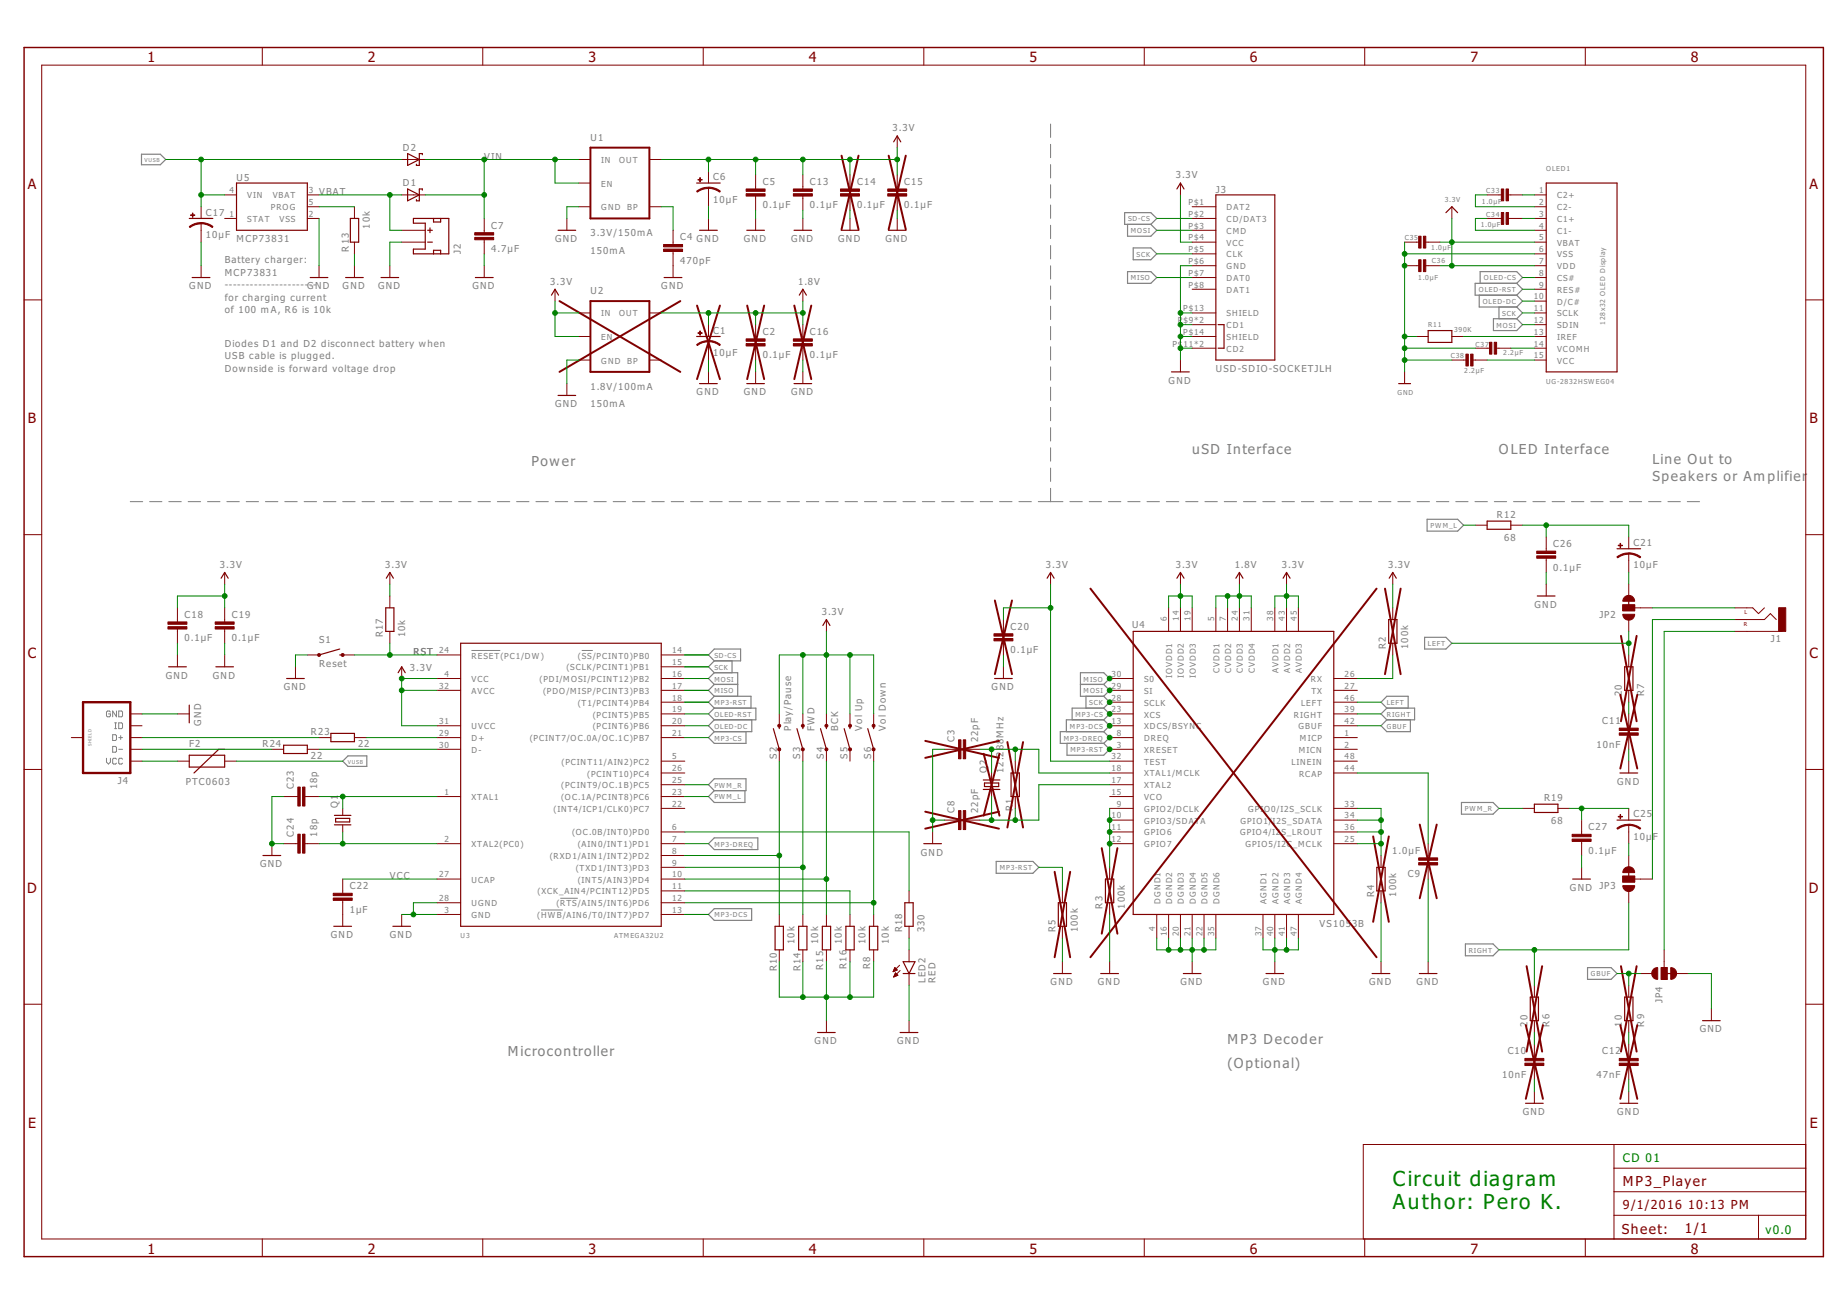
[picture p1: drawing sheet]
<svg xmlns="http://www.w3.org/2000/svg" width="297mm" height="210mm" viewBox="0 0 297 210" stroke-linecap="round" stroke-linejoin="round" font-family="sans-serif">
<defs><g id="words">
<g font-size="4" fill="#008000">
<text x="224" y="190.7">Circuit diagram</text>
<text x="224" y="194.5">Author: Pero K.</text>
</g>
<g font-size="2.8" fill="#800000">
<text x="23.7" y="10">1</text>
<text x="59.2" y="10">2</text>
<text x="94.6" y="10">3</text>
<text x="130.1" y="10">4</text>
<text x="165.6" y="10">5</text>
<text x="201" y="10">6</text>
<text x="236.5" y="10">7</text>
<text x="271.9" y="10">8</text>
<text x="4.5" y="30.3">A</text>
<text x="291" y="30.3">A</text>
<text x="4.5" y="68.1">B</text>
<text x="291" y="68.1">B</text>
<text x="4.5" y="105.8">C</text>
<text x="291" y="105.8">C</text>
<text x="4.4" y="143.6">D</text>
<text x="290.9" y="143.6">D</text>
<text x="4.5" y="181.4">E</text>
<text x="291.1" y="181.4">E</text>
<text x="23.7" y="201.7">1</text>
<text x="59.2" y="201.7">2</text>
<text x="94.6" y="201.7">3</text>
<text x="130.1" y="201.7">4</text>
<text x="165.6" y="201.7">5</text>
<text x="201" y="201.7">6</text>
<text x="236.5" y="201.7">7</text>
<text x="271.9" y="201.7">8</text>
</g>
<g font-size="2.7" fill="#808080">
<text x="85.5" y="75">Power</text>
<text x="191.7" y="73.1">uSD Interface</text>
<text x="241.1" y="73.1">OLED Interface</text>
<text x="265.7" y="74.6">Line Out to</text>
<text x="265.7" y="77.4">Speakers or Amplifier</text>
<text x="197.4" y="168">MP3 Decoder</text>
<text x="81.7" y="169.9">Microcontroller</text>
<text x="197.4" y="171.8">(Optional)</text>
</g>
<g font-size="2.7" fill="#800000">
<text x="261" y="190.7">MP3_Player</text>
<text x="260.8" y="198.4">Sheet:</text>
<text x="271" y="198.3">1/1</text>
</g>
<g font-size="2.4" fill="#800000">
<text x="261" y="194.5">9/1/2016</text>
<text x="271.5" y="194.5">10:13 PM</text>
</g>
<g font-size="2.3" fill="#008000">
<text x="261" y="186.9">CD 01</text>
<text x="284" y="198.5">v0.0</text>
</g>
<g font-size="1.9" fill="#808080">
<text x="95" y="22.6">U1</text>
<text x="143.5" y="21.1">3.3V</text>
<text x="38" y="29.1">U5</text>
<text x="64.8" y="29.9">D1</text>
<text x="64.8" y="24.2">D2</text>
<text x="77.9" y="25.7">VIN</text>
<text x="114.7" y="29">C6</text>
<text x="122.7" y="29.7">C5</text>
<text x="130.3" y="29.7">C13</text>
<text x="137.8" y="29.7">C14</text>
<text x="145.4" y="29.7">C15</text>
<text x="189.1" y="28.7">3.3V</text>
<text x="33.1" y="34.7">C17</text>
<text x="51.3" y="31.3">VBAT</text>
<text x="114.7" y="32.6">10µF</text>
<text x="122.7" y="33.5">0.1µF</text>
<text x="130.3" y="33.5">0.1µF</text>
<text x="137.8" y="33.5">0.1µF</text>
<text x="145.4" y="33.5">0.1µF</text>
<text x="195.5" y="31">J3</text>
<text x="33.1" y="38.3">10µF</text>
<text x="38" y="38.9">MCP73831</text>
<text x="56.1" y="40.5" transform="rotate(-90 56.1 40.5)">R13</text>
<text x="59.5" y="36.8" transform="rotate(-90 59.5 36.8)">10k</text>
<text x="74.1" y="40.8" transform="rotate(-90 74.1 40.8)">J2</text>
<text x="79" y="40.6">4.7μF</text>
<text x="79" y="36.8">C7</text>
<text x="89.3" y="38.9">GND</text>
<text x="95" y="40.8">150mA</text>
<text x="95" y="38">3.3V/150mA</text>
<text x="109.4" y="38.7">C4 GND</text>
<text x="119.6" y="38.9">GND</text>
<text x="127.2" y="38.9">GND</text>
<text x="134.8" y="38.9">GND</text>
<text x="142.4" y="38.9">GND</text>
<text x="30.4" y="46.5">GND</text>
<text x="36.1" y="42.4">Battery charger:</text>
<text x="36.1" y="44.4">MCP73831</text>
<text x="36.1" y="46.3">--------------------G--ND</text>
<text x="55.1" y="46.5">GND</text>
<text x="60.8" y="46.5">GND</text>
<text x="76" y="46.5">GND</text>
<text x="88.5" y="45.8">3.3V</text>
<text x="95" y="47.3">U2</text>
<text x="106.3" y="46.5">GND</text>
<text x="109.4" y="42.4">470pF</text>
<text x="128.4" y="45.8">1.8V</text>
<text x="36.1" y="48.3">for charging current</text>
<text x="36.1" y="50.3">of 100 mA, R6 is 10k</text>
<text x="114.7" y="53.6">C1</text>
<text x="122.7" y="53.8">C2</text>
<text x="130.3" y="53.8">C16</text>
<text x="36.1" y="55.8">Diodes D1 and D2 disconnect battery when</text>
<text x="36.1" y="57.8">USB cable is plugged.</text>
<text x="36.1" y="59.8">Downside is forward voltage drop</text>
<text x="114.7" y="57.2">10µF</text>
<text x="122.7" y="57.6">0.1µF</text>
<text x="130.3" y="57.6">0.1µF</text>
<text x="195.5" y="59.8">USD-SDIO-SOCKETJLH</text>
<text x="89.3" y="65.5">GND</text>
<text x="95" y="65.5">150mA</text>
<text x="95" y="62.7">1.8V/100mA</text>
<text x="112" y="63.6">GND</text>
<text x="119.6" y="63.6">GND</text>
<text x="127.2" y="63.6">GND</text>
<text x="187.9" y="61.7">GND</text>
<text x="240.7" y="83.4">R12</text>
<text x="241.9" y="86.9">68</text>
<text x="249.8" y="88">C26</text>
<text x="262.7" y="87.8">C21</text>
<text x="35.4" y="91.3">3.3V</text>
<text x="61.9" y="91.3">3.3V</text>
<text x="168.2" y="91.3">3.3V</text>
<text x="189.1" y="91.3">3.3V</text>
<text x="198.6" y="91.3">1.8V</text>
<text x="206.2" y="91.3">3.3V</text>
<text x="223.2" y="91.3">3.3V</text>
<text x="249.8" y="91.8">0.1µF</text>
<text x="262.7" y="91.4">10µF</text>
<text x="29.7" y="99.4">C18</text>
<text x="37.3" y="99.4">C19</text>
<text x="132.1" y="98.9">3.3V</text>
<text x="162.5" y="101.3">C20</text>
<text x="182.1" y="101">U4</text>
<text x="246.8" y="97.8">GND</text>
<text x="257.2" y="99.4">JP2</text>
<text x="29.7" y="103.2">0.1µF</text>
<text x="37.3" y="103.2">0.1µF</text>
<text x="51.3" y="107.2">Reset</text>
<text x="51.3" y="103.5">S1</text>
<text x="61.6" y="102.5" transform="rotate(-90 61.6 102.5)">R17</text>
<text x="65.2" y="102.5" transform="rotate(-90 65.2 102.5)">10k</text>
<text x="66.5" y="105.4">RST</text>
<text x="162.5" y="105.1">0.1µF</text>
<text x="222.9" y="104.4" transform="rotate(-90 222.9 104.4)">R2</text>
<text x="226.5" y="104.4" transform="rotate(-90 226.5 104.4)">100k</text>
<text x="284.8" y="103.3">J1</text>
<text x="26.6" y="109.1">GND</text>
<text x="34.2" y="109.1">GND</text>
<text x="45.6" y="111">GND</text>
<text x="65.9" y="108">3.3V</text>
<text x="159.5" y="111">GND</text>
<text x="260.8" y="112" transform="rotate(-90 260.8 112)">20</text>
<text x="264.4" y="112" transform="rotate(-90 264.4 112)">R7</text>
<text x="32.3" y="116.7" transform="rotate(-90 32.3 116.7)">GND</text>
<text x="50" y="118.3">R23</text>
<text x="127.2" y="117.5" transform="rotate(-90 127.2 117.5)">Play/Pause</text>
<text x="131" y="117.5" transform="rotate(-90 131 117.5)">FWD</text>
<text x="134.8" y="117.5" transform="rotate(-90 134.8 117.5)">BCK</text>
<text x="138.7" y="117.5" transform="rotate(-90 138.7 117.5)">Vol Up</text>
<text x="142.5" y="117.5" transform="rotate(-90 142.5 117.5)">Vol Down</text>
<text x="153.5" y="119.4" transform="rotate(-90 153.5 119.4)">C3</text>
<text x="157.3" y="119.4" transform="rotate(-90 157.3 119.4)">22pF</text>
<text x="257.7" y="116.5">C11</text>
<text x="30.4" y="120.2">F2</text>
<text x="42.2" y="120.2">R24</text>
<text x="50" y="122">22</text>
<text x="57.6" y="120.2">22</text>
<text x="124.9" y="122" transform="rotate(-90 124.9 122)">S2</text>
<text x="128.7" y="122" transform="rotate(-90 128.7 122)">S3</text>
<text x="132.5" y="122" transform="rotate(-90 132.5 122)">S4</text>
<text x="136.3" y="122" transform="rotate(-90 136.3 122)">S5</text>
<text x="140.1" y="122" transform="rotate(-90 140.1 122)">S6</text>
<text x="158.7" y="124.3" transform="rotate(-90 158.7 124.3)">Q2</text>
<text x="161.4" y="124.3" transform="rotate(-90 161.4 124.3)">12.288MHz</text>
<text x="256.8" y="120.2">10nF</text>
<text x="19" y="126">J4</text>
<text x="29.9" y="126.2">PTC0603</text>
<text x="47.2" y="127" transform="rotate(-90 47.2 127)">C23</text>
<text x="51" y="127" transform="rotate(-90 51 127)">18p</text>
<text x="54.3" y="130" transform="rotate(-90 54.3 130)">Q1</text>
<text x="153.5" y="130.8" transform="rotate(-90 153.5 130.8)">C8</text>
<text x="157.3" y="130.8" transform="rotate(-90 157.3 130.8)">22pF</text>
<text x="162.9" y="130.5" transform="rotate(-90 162.9 130.5)">R1</text>
<text x="248.3" y="128.9">R19</text>
<text x="260.1" y="126.2">GND</text>
<text x="262.7" y="131.4">C25</text>
<text x="47.2" y="134.6" transform="rotate(-90 47.2 134.6)">C24</text>
<text x="51" y="134.6" transform="rotate(-90 51 134.6)">18p</text>
<text x="148.1" y="137.6">GND</text>
<text x="223.9" y="137.3">1.0µF</text>
<text x="249.5" y="132.5">68</text>
<text x="255.5" y="137.3">0.1µF</text>
<text x="255.5" y="133.5">C27</text>
<text x="262.7" y="135">10µ</text>
<text x="265.8" y="135">F</text>
<text x="41.8" y="139.5">GND</text>
<text x="56.2" y="143">C22</text>
<text x="62.7" y="141.4">VCC</text>
<text x="226.4" y="141.1">C9</text>
<text x="252.5" y="143.3">GND JP3</text>
<text x="56.2" y="146.8">1µF</text>
<text x="145.1" y="149.9" transform="rotate(-90 145.1 149.9)">R18</text>
<text x="148.7" y="149.9" transform="rotate(-90 148.7 149.9)">330</text>
<text x="169.7" y="149.9" transform="rotate(-90 169.7 149.9)">R5</text>
<text x="173.3" y="149.9" transform="rotate(-90 173.3 149.9)">100k</text>
<text x="177.3" y="146.1" transform="rotate(-90 177.3 146.1)">R3</text>
<text x="180.9" y="146.1" transform="rotate(-90 180.9 146.1)">100k</text>
<text x="212.2" y="149.2">VS1053B</text>
<text x="221" y="144.2" transform="rotate(-90 221 144.2)">R4</text>
<text x="224.6" y="144.2" transform="rotate(-90 224.6 144.2)">100k</text>
<text x="53.2" y="150.9">GND</text>
<text x="62.7" y="150.9">GND</text>
<text x="127.8" y="151.8" transform="rotate(-90 127.8 151.8)">10k</text>
<text x="131.6" y="151.8" transform="rotate(-90 131.6 151.8)">10k</text>
<text x="135.4" y="151.8" transform="rotate(-90 135.4 151.8)">10k</text>
<text x="136.2" y="155.8" transform="rotate(-90 136.2 155.8)">R16</text>
<text x="139.2" y="151.8" transform="rotate(-90 139.2 151.8)">10k</text>
<text x="139.9" y="155.8" transform="rotate(-90 139.9 155.8)">R8</text>
<text x="143" y="151.8" transform="rotate(-90 143 151.8)">10k</text>
<text x="125" y="156.2" transform="rotate(-90 125 156.2)">R10</text>
<text x="128.8" y="156.2" transform="rotate(-90 128.8 156.2)">R14</text>
<text x="132.4" y="156" transform="rotate(-90 132.4 156)">R15</text>
<text x="148.8" y="158.1" transform="rotate(-90 148.8 158.1)">LED2</text>
<text x="150.5" y="158.1" transform="rotate(-90 150.5 158.1)">RED</text>
<text x="169" y="158.5">GND</text>
<text x="176.6" y="158.5">GND</text>
<text x="189.8" y="158.5">GND</text>
<text x="203.1" y="158.5">GND</text>
<text x="220.2" y="158.5">GND</text>
<text x="227.8" y="158.5">GND</text>
<text x="267.4" y="161.3" transform="rotate(-90 267.4 161.3)">JP4</text>
<text x="131" y="168">GND</text>
<text x="144.3" y="168">GND</text>
<text x="245.6" y="165.1" transform="rotate(-90 245.6 165.1)">20</text>
<text x="249.2" y="165.1" transform="rotate(-90 249.2 165.1)">R6</text>
<text x="260.8" y="165.1" transform="rotate(-90 260.8 165.1)">10</text>
<text x="264.4" y="165.1" transform="rotate(-90 264.4 165.1)">R9</text>
<text x="273.4" y="166.1">GND</text>
<text x="241.6" y="173.4">10nF</text>
<text x="242.5" y="169.6">C10</text>
<text x="256.8" y="173.4">47nF</text>
<text x="257.7" y="169.6">C12</text>
<text x="244.9" y="179.4">GND</text>
<text x="260.1" y="179.4">GND</text>
</g>
<g font-size="1.6" fill="#808080">
<text x="96.7" y="26.2">IN</text>
<text x="99.6" y="26.2">OUT</text>
<text x="36.9" y="31.1">4</text>
<text x="36.9" y="34.9">1</text>
<text x="39.8" y="31.9">VIN</text>
<text x="39.8" y="35.7">STAT</text>
<text x="43.6" y="33.8">PROG</text>
<text x="43.9" y="31.9">VBAT</text>
<text x="44.9" y="35.7">VSS</text>
<text x="49.7" y="31.1">3</text>
<text x="49.7" y="33">5</text>
<text x="49.7" y="34.9">2</text>
<text x="96.7" y="33.8">GND BP</text>
<text x="96.7" y="30">EN</text>
<text x="191.2" y="34.9">P$2</text>
<text x="191.2" y="33">P$1</text>
<text x="197.3" y="35.7">CD/DAT3</text>
<text x="197.3" y="33.8">DAT2</text>
<text x="247.5" y="31.1">1</text>
<text x="247.5" y="33">2</text>
<text x="247.5" y="34.9">3</text>
<text x="250.4" y="31.9">C2+</text>
<text x="250.4" y="33.8">C2-</text>
<text x="250.4" y="35.7">C1+</text>
<text x="191.2" y="36.8">P$3</text>
<text x="191.2" y="38.7">P$4</text>
<text x="191.2" y="40.6">P$5</text>
<text x="197.3" y="37.6">CMD</text>
<text x="197.3" y="39.5">VCC</text>
<text x="197.3" y="41.4">CLK</text>
<text x="247.5" y="36.8">4</text>
<text x="247.5" y="38.7">5</text>
<text x="247.5" y="40.6">6</text>
<text x="250.4" y="37.6">C1-</text>
<text x="250.4" y="39.5">VBAT</text>
<text x="250.4" y="41.4">VSS</text>
<text x="191.2" y="42.5">P$6</text>
<text x="191.2" y="46.3">P$8</text>
<text x="191.2" y="44.4">P$7</text>
<text x="197.3" y="43.3">GND</text>
<text x="197.3" y="47.1">DAT1</text>
<text x="197.3" y="45.2">DAT0</text>
<text x="247.5" y="42.5">7</text>
<text x="247.5" y="44.4">8</text>
<text x="247.5" y="46.3">9</text>
<text x="250.4" y="43.3">VDD</text>
<text x="250.4" y="45.2">CS#</text>
<text x="250.4" y="47.1">RES#</text>
<text x="96.7" y="50.9">IN</text>
<text x="99.6" y="50.9">OUT</text>
<text x="189.4" y="52">P$9*2</text>
<text x="190.3" y="53.9">P$14</text>
<text x="190.3" y="50.1">P$13</text>
<text x="197.3" y="50.9">SHIELD</text>
<text x="197.3" y="52.8">CD1</text>
<text x="246.7" y="48.2">10</text>
<text x="246.7" y="50.1">11</text>
<text x="246.7" y="52">12</text>
<text x="246.7" y="53.9">13</text>
<text x="250.4" y="49">D/C#</text>
<text x="250.4" y="50.9">SCLK</text>
<text x="250.4" y="52.8">SDIN</text>
<text x="96.7" y="58.5">GND BP</text>
<text x="96.7" y="54.7">EN</text>
<text x="188.6" y="55.8">P$11*2</text>
<text x="197.3" y="54.7">SHIELD</text>
<text x="197.3" y="56.6">CD2</text>
<text x="246.7" y="55.8">14</text>
<text x="246.7" y="57.6">15</text>
<text x="250.4" y="54.7">IREF</text>
<text x="250.4" y="56.6">VCOMH</text>
<text x="250.4" y="58.5">VCC</text>
<text x="187.7" y="99.8" transform="rotate(-90 187.7 99.8)">6</text>
<text x="189.6" y="99.8" transform="rotate(-90 189.6 99.8)">14</text>
<text x="191.5" y="99.8" transform="rotate(-90 191.5 99.8)">19</text>
<text x="195.3" y="99.8" transform="rotate(-90 195.3 99.8)">5</text>
<text x="197.2" y="99.8" transform="rotate(-90 197.2 99.8)">7</text>
<text x="199.1" y="99.8" transform="rotate(-90 199.1 99.8)">24</text>
<text x="201" y="99.8" transform="rotate(-90 201 99.8)">31</text>
<text x="204.8" y="99.8" transform="rotate(-90 204.8 99.8)">38</text>
<text x="206.6" y="99.8" transform="rotate(-90 206.6 99.8)">43</text>
<text x="208.5" y="99.8" transform="rotate(-90 208.5 99.8)">45</text>
<text x="70.6" y="105.1">24</text>
<text x="75.8" y="105.9">RESET(PC1/DW)</text>
<text x="91.1" y="107.8">(SCLK/PCINT1)PB1</text>
<text x="92.9" y="105.9">(SS/PCINT0)PB0</text>
<text x="108.1" y="105.1">14</text>
<text x="108.1" y="107">15</text>
<text x="70.6" y="110.8">32</text>
<text x="71.5" y="108.9">4</text>
<text x="75.8" y="109.7">VCC</text>
<text x="75.8" y="111.6">AVCC</text>
<text x="86.8" y="109.7">(PDI/MOSI/PCINT12)PB2</text>
<text x="87.3" y="111.6">(PDO/MISP/PCINT3)PB3</text>
<text x="92.9" y="113.5">(T1/PCINT4)PB4</text>
<text x="108.1" y="108.9">16</text>
<text x="108.1" y="110.8">17</text>
<text x="108.1" y="112.7">18</text>
<text x="178.8" y="108.9">30</text>
<text x="178.8" y="110.8">29</text>
<text x="178.8" y="112.7">28</text>
<text x="184" y="109.7">S0</text>
<text x="184" y="111.6">SI</text>
<text x="184" y="113.5">SCLK</text>
<text x="188.5" y="109.1" transform="rotate(-90 188.5 109.1)">IOVDD1</text>
<text x="190.4" y="109.1" transform="rotate(-90 190.4 109.1)">IOVDD2</text>
<text x="192.3" y="109.1" transform="rotate(-90 192.3 109.1)">IOVDD3</text>
<text x="196.1" y="108.3" transform="rotate(-90 196.1 108.3)">CVDD1</text>
<text x="198" y="108.3" transform="rotate(-90 198 108.3)">CVDD2</text>
<text x="199.9" y="108.3" transform="rotate(-90 199.9 108.3)">CVDD3</text>
<text x="201.8" y="108.3" transform="rotate(-90 201.8 108.3)">CVDD4</text>
<text x="205.6" y="108.3" transform="rotate(-90 205.6 108.3)">AVDD1</text>
<text x="207.5" y="108.3" transform="rotate(-90 207.5 108.3)">AVDD2</text>
<text x="209.3" y="113.5">LEFT</text>
<text x="209.4" y="108.3" transform="rotate(-90 209.4 108.3)">AVDD3</text>
<text x="210.8" y="109.7">RX</text>
<text x="210.9" y="111.6">TX</text>
<text x="216.2" y="108.9">26</text>
<text x="216.2" y="110.8">27</text>
<text x="216.2" y="112.7">46</text>
<text x="70.6" y="116.5">31</text>
<text x="70.6" y="118.4">29</text>
<text x="75.8" y="117.3">UVCC</text>
<text x="75.8" y="119.2">D+</text>
<text x="85.2" y="119.2">(PCINT7/OC.0A/OC.1C)PB7</text>
<text x="95.3" y="115.4">(PCINT5)PB5</text>
<text x="95.3" y="117.3">(PCINT6)PB6</text>
<text x="108.1" y="114.6">19</text>
<text x="108.1" y="116.5">20</text>
<text x="108.1" y="118.4">21</text>
<text x="178.8" y="114.6">23</text>
<text x="178.8" y="116.5">13</text>
<text x="179.6" y="118.4">8</text>
<text x="184" y="115.4">XCS</text>
<text x="184" y="117.3">XDCS/BSYNC</text>
<text x="184" y="119.2">DREQ</text>
<text x="208.1" y="115.4">RIGHT</text>
<text x="208.8" y="117.3">GBUF</text>
<text x="209.1" y="119.2">MICP</text>
<text x="216.2" y="114.6">39</text>
<text x="216.2" y="116.5">42</text>
<text x="216.2" y="118.4">1</text>
<text x="70.6" y="120.3">30</text>
<text x="75.8" y="121.1">D-</text>
<text x="90.3" y="123">(PCINT11/AIN2)PC2</text>
<text x="94.4" y="124.9">(PCINT10)PC4</text>
<text x="108.1" y="122.2">5</text>
<text x="108.1" y="124.1">26</text>
<text x="108.1" y="126">25</text>
<text x="178.8" y="122.2">32</text>
<text x="178.8" y="124.1">18</text>
<text x="178.8" y="126">17</text>
<text x="179.6" y="120.3">3</text>
<text x="184" y="121.1">XRESET</text>
<text x="184" y="123">TEST</text>
<text x="184" y="124.9">XTAL1/MCLK</text>
<text x="207.7" y="123">LINEIN</text>
<text x="208.9" y="121.1">MICN</text>
<text x="208.9" y="124.9">RCAP</text>
<text x="216.2" y="120.3">2</text>
<text x="216.2" y="122.2">48</text>
<text x="216.2" y="124.1">44</text>
<text x="71.5" y="127.9">1</text>
<text x="75.8" y="128.7">XTAL1</text>
<text x="89" y="130.6">(INT4/ICP1/CLK0)PC7</text>
<text x="90.2" y="128.7">(OC.1A/PCINT8)PC6</text>
<text x="90.3" y="126.8">(PCINT9/OC.1B)PC5</text>
<text x="108.1" y="127.9">23</text>
<text x="108.1" y="129.8">22</text>
<text x="178.8" y="127.9">15</text>
<text x="178.8" y="131.6">10</text>
<text x="179.6" y="129.8">9</text>
<text x="184" y="126.8">XTAL2</text>
<text x="184" y="128.7">VCO</text>
<text x="184" y="130.6">GPIO2/DCLK</text>
<text x="200.7" y="130.6">GPIO0/I2S_SCLK</text>
<text x="216.2" y="129.8">33</text>
<text x="216.2" y="131.6">34</text>
<text x="71.5" y="135.4">2</text>
<text x="75.8" y="136.3">XTAL2(PC0)</text>
<text x="92" y="134.4">(OC.0B/INT0)PD0</text>
<text x="92.9" y="136.3">(AIN0/INT1)PD1</text>
<text x="108.1" y="133.5">6</text>
<text x="108.1" y="137.3">8</text>
<text x="108.1" y="135.4">7</text>
<text x="178.8" y="133.5">11</text>
<text x="178.8" y="135.4">12</text>
<text x="184" y="132.5">GPIO3/SDATA</text>
<text x="184" y="134.4">GPIO6</text>
<text x="184" y="136.3">GPIO7</text>
<text x="199.4" y="134.4">GPIO4/I2S_LROUT</text>
<text x="199.5" y="132.5">GPIO1/I2S_SDATA</text>
<text x="200.3" y="136.3">GPIO5/I2C_MCLK</text>
<text x="216.2" y="133.5">36</text>
<text x="216.2" y="135.4">25</text>
<text x="70.6" y="141.1">27</text>
<text x="75.8" y="142">UCAP</text>
<text x="86.5" y="143.9">(XCK_AIN4/PCINT12)PD5</text>
<text x="88.4" y="138.2">(RXD1/AIN1/INT2)PD2</text>
<text x="92.6" y="140.1">(TXD1/INT3)PD3</text>
<text x="92.9" y="142">(INT5/AIN3)PD4</text>
<text x="108.1" y="139.2">9</text>
<text x="108.1" y="141.1">10</text>
<text x="108.1" y="143">11</text>
<text x="70.6" y="144.9">28</text>
<text x="71.5" y="146.8">3</text>
<text x="75.8" y="145.8">UGND</text>
<text x="75.8" y="147.7">GND</text>
<text x="86.4" y="147.7">(HWB/AIN6/T0/INT7)PD7</text>
<text x="89.5" y="145.8">(RTS/AIN5/INT6)PD6</text>
<text x="108.1" y="144.9">12</text>
<text x="108.1" y="146.8">13</text>
<text x="185.8" y="149.7" transform="rotate(-90 185.8 149.7)">4</text>
<text x="186.6" y="145.3" transform="rotate(-90 186.6 145.3)">DGND1</text>
<text x="188.5" y="145.3" transform="rotate(-90 188.5 145.3)">DGND2</text>
<text x="190.4" y="145.3" transform="rotate(-90 190.4 145.3)">DGND3</text>
<text x="192.3" y="145.3" transform="rotate(-90 192.3 145.3)">DGND4</text>
<text x="194.2" y="145.3" transform="rotate(-90 194.2 145.3)">DGND5</text>
<text x="196.1" y="145.3" transform="rotate(-90 196.1 145.3)">DGND6</text>
<text x="203.7" y="145.3" transform="rotate(-90 203.7 145.3)">AGND1</text>
<text x="205.6" y="145.3" transform="rotate(-90 205.6 145.3)">AGND2</text>
<text x="207.5" y="145.3" transform="rotate(-90 207.5 145.3)">AGND3</text>
<text x="209.4" y="145.3" transform="rotate(-90 209.4 145.3)">AGND4</text>
<text x="187.7" y="150.6" transform="rotate(-90 187.7 150.6)">16</text>
<text x="189.6" y="150.6" transform="rotate(-90 189.6 150.6)">20</text>
<text x="191.5" y="150.6" transform="rotate(-90 191.5 150.6)">21</text>
<text x="193.4" y="150.6" transform="rotate(-90 193.4 150.6)">22</text>
<text x="195.3" y="150.6" transform="rotate(-90 195.3 150.6)">35</text>
<text x="202.9" y="150.6" transform="rotate(-90 202.9 150.6)">37</text>
<text x="204.8" y="150.6" transform="rotate(-90 204.8 150.6)">40</text>
<text x="206.6" y="150.6" transform="rotate(-90 206.6 150.6)">41</text>
<text x="208.5" y="150.6" transform="rotate(-90 208.5 150.6)">47</text>
</g>
<g font-size="1.3" fill="#808080">
<text x="248.7" y="27.6">OLED1</text>
<text x="181.4" y="35.6">SD-CS</text>
<text x="232.3" y="32.5">3.3V</text>
<text x="238.3" y="32.9">1.0µF</text>
<text x="239" y="31">C33</text>
<text x="239" y="35">C34</text>
<text x="181.9" y="37.5">MOSI</text>
<text x="182.8" y="41.3">SCK</text>
<text x="225.9" y="38.6">C35</text>
<text x="230.2" y="40.3">1.0µF</text>
<text x="238.1" y="36.5">1.0µF</text>
<text x="181.9" y="45.1">MISO</text>
<text x="228.1" y="45">1.0µF</text>
<text x="230.3" y="42.4">C36</text>
<text x="237.8" y="47">OLED-RST</text>
<text x="238.6" y="45.1">OLED-CS</text>
<text x="229.7" y="52.6">R11</text>
<text x="233.9" y="53.5">390K</text>
<text x="238.5" y="48.9">OLED-DC</text>
<text x="240.7" y="52.7">MOSI</text>
<text x="241.6" y="50.8">SCK</text>
<text x="258.1" y="52.2" transform="rotate(-90 258.1 52.2)">128x32 OLED Display</text>
<text x="233.3" y="57.5">C38</text>
<text x="237.3" y="55.8">C37</text>
<text x="241.8" y="57.2">2.2µF</text>
<text x="224.8" y="63.6">GND</text>
<text x="235.5" y="60">2.2µF</text>
<text x="248.7" y="61.7">UG-2832HSWEG04</text>
<text x="230.1" y="85">PWM_L</text>
<text x="114.9" y="107.7">SCK</text>
<text x="114.9" y="105.8">SD-CS</text>
<text x="229.7" y="103.9">LEFT</text>
<text x="114.9" y="109.6">MOSI</text>
<text x="114.9" y="111.5">MISO</text>
<text x="114.9" y="113.4">MP3-RST</text>
<text x="174.3" y="111.5">MOSI</text>
<text x="174.3" y="109.6">MISO</text>
<text x="175.2" y="113.4">SCK</text>
<text x="223" y="113.4">LEFT</text>
<text x="114.9" y="119.1">MP3-CS</text>
<text x="114.9" y="115.3">OLED-RST</text>
<text x="114.9" y="117.2">OLED-DC</text>
<text x="171.1" y="119.1">MP3-DREQ</text>
<text x="172.1" y="117.2">MP3-DCS</text>
<text x="173" y="115.3">MP3-CS</text>
<text x="223" y="115.3">RIGHT</text>
<text x="223" y="117.2">GBUF</text>
<text x="172.2" y="121">MP3-RST</text>
<text x="114.9" y="126.7">PWM_R</text>
<text x="114.9" y="128.6">PWM_L</text>
<text x="235.6" y="130.5">PWM_R</text>
<text x="114.9" y="136.2">MP3-DREQ</text>
<text x="160.8" y="140">MP3-RST</text>
<text x="114.9" y="147.6">MP3-DCS</text>
<text x="74.1" y="150.9">U3</text>
<text x="98.8" y="150.9">ATMEGA32U2</text>
<text x="236.2" y="153.3">RIGHT</text>
<text x="255.9" y="157.1">GBUF</text>
</g>
<g font-size="1.1" fill="#808080">
<text x="23.3" y="26">VUSB</text>
<text x="56" y="122.8">VUSB</text>
</g>
<g font-size="1.1" fill="#800000">
<text x="280.5" y="100.6">R</text>
<text x="280.6" y="98.7">L</text>
</g>
<text font-size=".8" fill="#808080" x="14.7" y="120.1" transform="rotate(-90 14.7 120.1)">SHIELD</text>
</g></defs>
<g fill="none" stroke="#808080" stroke-width=".17">
<path d="M169 20v2.1M169 23.2v2.2M169 26.5v2.1M169 29.7v2.2M169 33v2.1M169 36.2v2.2M169 39.5v2.1M169 42.8v2.1M169 46v2.1M169 49.3v2.1M169 52.5v2.2M169 55.8v2.1"/>
<path d="M169 59v2.2M169 62.3v2.1M169 65.5v2.2M169 68.8v2.1M169 72v2.2M169 75.3v2.1M169 78.5v2.2M21 80.7h1.9M24.1 80.7h1.9M27.2 80.7h1.9M30.3 80.7h2M33.4 80.7h2"/>
<path d="M36.5 80.7h2M39.6 80.7h2M42.7 80.7h2M45.8 80.7h2M48.9 80.7h2M52 80.7h2M55.1 80.7h2M58.2 80.7h2M61.3 80.7h2M64.5 80.7h1.9M67.6 80.7h1.9M70.7 80.7h1.9"/>
<path d="M73.8 80.7h2M76.9 80.7h2M80 80.7h2M83.1 80.7h2M86.2 80.7h2M89.3 80.7h2M92.4 80.7h2M95.5 80.7h2M98.6 80.7h2M101.7 80.7h2M104.8 80.7h2M107.9 80.7h2"/>
<path d="M111.1 80.7h1.9M114.2 80.7h1.9M117.3 80.7h2M120.4 80.7h2M123.5 80.7h2M126.6 80.7h2M129.7 80.7h2M132.8 80.7h2M135.9 80.7h2M139 80.7h2M142.1 80.7h2M145.2 80.7h2"/>
<path d="M148.3 80.7h2M151.4 80.7h2M154.5 80.7h2M157.6 80.7h2M160.8 80.7h2M163.9 80.7h2M167 80.7h3.9M172.1 80.7h2M175.2 80.7h1.9M178.3 80.7h2M181.4 80.7h1.9M184.5 80.7h2"/>
<path d="M187.6 80.7h2M190.7 80.7h2M193.8 80.7h2M196.9 80.7h2M200 80.7h2M203.1 80.7h2M206.2 80.7h2M209.3 80.7h2M212.4 80.7h2M215.5 80.7h2M218.6 80.7h2M221.7 80.7h2"/>
<path d="M224.8 80.7h2M227.9 80.7h2M231 80.7h2M234.1 80.7h2M237.2 80.7h2M240.3 80.7h2M243.4 80.7h2M246.5 80.7h2M249.6 80.7h2M252.7 80.7h2M255.8 80.7h2M258.9 80.7h2"/>
<path d="M262 80.7h2M265.1 80.7h2M268.2 80.7h2M271.4 80.7h1.9"/>
</g>
<g fill="none" stroke="#808080" stroke-width=".16">
<path d="M17.8 114.5l-.2-.1h-.3l-.2 .1v.6l.2 .2h.3l.2-.2v-.3h-.4M18.1 118.2h.5l.1 .1v.6l-.1 .2h-.5zM18.4 117.2h.4M18.4 116.3h.4M18.6 116.3v.9M18.7 114.4v.9l-.6-.9v.9M19.1 114.4h.5l.1 .1v.6l-.1 .2h-.5zM19.1 116.3h.5l.1 .1v.7l-.1 .1h-.5zM19.1 118.6h.6M19.4 118.3v.6M75.8 104.6h4.7M93.6 104.6h1.7"/>
<path d="M17.1 122v.6l.3 .3 .4-.3v-.6M18.1 120.1h.5l.1 .1v.6l-.1 .2h-.5zM18.7 122.1l-.1-.1h-.3l-.2 .1v.6l.2 .2h.3l.1-.2M19.1 120.5h.6M19.7 122.1l-.1-.1h-.4l-.1 .1v.6l.1 .2h.4l.1-.2M87 146.4h3.5M90.1 144.5h2.8"/>
</g>
<g fill="none" stroke="#808080" stroke-width=".19">
<path d="M22.8 24.8h3l.8 .9-.8 .8h-3zM180.9 34.2h4.2l.9 .9-.9 1h-4.2zM181.3 36.1v1.9h3.8l.9-1-.9-.9M182.2 39.9h2.9l.9 .9-.9 1h-2.9zM181.3 43.7h3.8l.9 .9-.9 1h-3.8zM237.9 47.5v1.9h6M238 45.6v-1.9h5.9l1 .9-1 1M240.2 51.3h3.7l1 .9-1 1h-3.7zM241.1 49.4v1.9M243.9 49.4l1 .9-1 1M243.9 45.6h-6.7v1.9h6.7M243.9 45.6l1 .9-1 1"/>
<path d="M243.9 47.5l1 .9-1 1M229.5 83.5h4.9l1 1-1 .9h-4.9zM114.9 112h5.9v1.9M114.9 113.9h6.7v1.9h-6.7M114.9 104.4h4.2v1.9h-4.2l-1-1zM114.9 110.1h3.7M114.9 108.2l-1 .9 1 1M114.9 108.2h3.7v3.8M114.9 106.3l-1 1 1 .9M114.9 110.1l-1 .9 1 1M114.9 117.7l-1 .9 1 1h5.1v-1.9M114.9 112l-1 .9 1 1"/>
<path d="M114.9 113.9l-1 .9 1 1M114.9 115.8l-1 .9 1 1M117.7 106.3v1.9M120.9 115.8v1.9h-6M171.6 119.6v1.9h5.9l1-1-1-.9M173.8 110.1h3.7M174.6 112v1.9M177.5 110.1l1-1-1-.9h-3.7v3.8h3.7M177.5 113.9h-5.1v1.9M177.5 115.8h-6v1.9M177.5 117.7h-7v1.9h7M177.5 110.1l1 .9-1 1"/>
<path d="M177.5 112l1 .9-1 1M177.5 115.8l1 .9-1 1M177.5 113.9l1 .9-1 1M177.5 117.7l1 .9-1 1M223 113.9l-.9-1 .9-.9h3.5v1.9M223 113.9h4.5v1.9h-4.5M223 113.9l-.9 .9 .9 1M223 115.8l-.9 .9 .9 1h3.8v-1.9M229.1 102.5h3.4l1 1-1 .9h-3.4zM55.1 122.4l.9-.8h3v1.7h-3zM113.9 135.7l1-.9h7v1.9h-7zM114.9 125.3h5.1v1.9h-5.1l-1-1z"/>
<path d="M114.9 127.2l-1 .9 1 1h4.9v-1.9M160.2 138.6h5.9l1 .9-1 1h-5.9zM235 129.1h5.1l1 .9-1 1h-5.1zM113.9 147.1l1-.9h6v1.8h-6zM235.7 151.8h4.4l1 1-1 .9h-4.4zM255.3 155.6h3.8l1 1-1 .9h-3.8z"/>
</g>
<g fill="none" stroke="#800000" stroke-width=".32">
<path d="M95 23.7h9.4v11.4h-9.4zM135.3 25l2.8 11.9M138.1 25l-2.8 11.9M142.9 25l2.8 11.9M145.7 25l-2.8 11.9M90 48.4l19.4 11.4M95 48.4h9.4v11.4h-9.4zM109.4 48.4l-19.4 11.4M112.1 49.1l3.7 11.9M115.8 49.1l-3.7 11.9M120.2 49.1l2.7 11.9M122.9 49.1l-2.7 11.9"/>
<path d="M127.7 49.1l2.8 11.9M130.5 49.1l-2.8 11.9M160 96.6l2.8 11.8M162.8 96.6l-2.8 11.8M175.4 94.7l46 59.3M221.4 94.7l-46 59.3M222.7 94.7l2.6 13.7M225.3 94.7l-2.6 13.7M148.8 119.2l11.9 2.7M160.7 119.2l-11.9 2.7M162 119.4l2.5 13.7M164.5 119.4l-2.5 13.7"/>
<path d="M260.6 111.8l2.7 11.8M260.7 102.3l2.5 13.7M263.2 102.3l-2.5 13.7M263.3 111.8l-2.7 11.8M148.8 130.6l11.9 2.7M158.2 121.2l2.5 10M160.7 130.6l-11.9 2.7M160.7 121.2l-2.5 10M177.2 136.4l2.5 13.8M179.7 136.4l-2.5 13.8M220.8 134.5l2.6 13.8M223.4 134.5l-2.6 13.8"/>
<path d="M228.3 132.6l2.8 11.9M231.1 132.6l-2.8 11.9M169.6 140.2l2.5 13.8M172.1 140.2l-2.5 13.8M245.5 155.4l2.5 13.7M248 155.4l-2.5 13.7M260.7 155.4l2.5 13.7M263.2 155.4l-2.5 13.7M245.4 164.9l2.7 11.8M248.1 164.9l-2.7 11.8M260.6 164.9l2.7 11.8M263.3 164.9l-2.7 11.8"/>
</g>
<g fill="none" stroke="#800000" stroke-width=".16">
<path d="M6.7 10.5h283.7v188.8h-283.7zM42.2 7.6v2.9M77.6 7.6v2.9M113.1 7.6v2.9M148.6 7.6v2.9M184 7.6v2.9M219.5 7.6v2.9M255 7.6v2.9M32.3 33.3v1.8M32.3 35.9v3M36.1 31.3h1.9M36.1 35.1h1.9"/>
<path d="M49.4 33.3h1.9M49.4 31.3h1.9M49.4 35.1h1.9M57 33.3v1.8M57 38.9v1.9M64.6 25.7h3.8M64.6 31.3h3.8M64.6 38.9h3.8M64.6 37h3.8M77.9 35.1v2.3M77.9 38.6v2.2M91.2 35.1v1.9"/>
<path d="M93.1 25.7h1.9M93.1 33.3h1.9M93.1 29.4h1.9M104.4 25.7h1.9M104.4 33.3h1.9M108.2 37v2.3M113.9 27.6v1.8M113.9 30.2v3.1M113.9 35.1v1.9M121.5 28.1v2.3M121.5 31.5v2.3M121.5 35.1v1.9"/>
<path d="M129.1 28.1v2.3M129.1 31.5v2.3M129.1 35.1v1.9M136.7 28.1v2.3M136.7 31.5v2.3M136.7 35.1v1.9M144.3 21.9v1.8M144.3 28.1v2.3M144.3 31.5v2.3M144.3 35.1v1.9M189.8 29.4v1.9M191.7 33.3h3.8"/>
<path d="M191.7 35.1h3.8M191.7 38.9h3.8M191.7 37h3.8M225.9 38.9h2.4M229.1 38.9h2.5M233.5 33.3v1.8M239.2 31.3h2.4M239.2 35.1h2.4M242.4 31.3h2.5M242.4 35.1h2.5M246.8 33.3h1.9M246.8 31.3h1.9"/>
<path d="M246.8 35.1h1.9M246.8 38.9h1.9M246.8 37h1.9M3.9 48.2h2.8M32.3 42.7v1.9M51.3 42.7v1.9M57 42.7v1.9M62.7 42.7v1.9M77.9 42.7v1.9M89.3 46.5v1.9M93.1 50.3h1.9M93.1 57.9h1.9"/>
<path d="M93.1 54.1h1.9M104.4 50.3h1.9M104.4 57.9h1.9M108.2 40.4v4.2M113.9 52.2v1.9M113.9 54.9v3M113.9 59.8v1.9M121.5 52.2v2.3M121.5 55.6v2.3M121.5 59.8v1.9M129.1 46.5v1.9M129.1 52.2v2.3"/>
<path d="M129.1 55.6v2.3M129.1 59.8v1.9M189.8 57.9v1.9M191.7 50.3h3.8M191.7 54.1h3.8M191.7 40.8h3.8M191.7 42.7h3.8M191.7 44.6h3.8M191.7 46.5h3.8M191.7 52.2h3.8M191.7 56h3.8M225.9 42.7h2.4"/>
<path d="M225.9 59.8v1.9M227.8 54.1h1.9M229.1 42.7h2.5M233.5 57.9h2.4M233.5 54.1h1.9M236.7 57.9h2.5M237.3 56h2.4M240.5 56h2.5M246.8 50.3h1.9M246.8 57.9h1.9M246.8 54.1h1.9M246.8 40.8h1.9"/>
<path d="M246.8 42.7h1.9M246.8 44.6h1.9M246.8 46.5h1.9M246.8 48.4h1.9M246.8 52.2h1.9M246.8 56h1.9M290.4 48.2h2.8M91.2 61.7v1.9M3.9 86h2.8M28.5 97.8v2.2M36.1 92.1v1.9M36.1 97.8v2.2"/>
<path d="M62.7 92.1v1.9M62.7 95.9v1.9M132.9 99.7v1.9M161.4 99.7v2.2M169 92.1v1.9M187.9 97.8v3.8M189.8 92.1v1.9M189.8 97.8v3.8M191.7 97.8v3.8M195.5 97.8v3.8M197.4 97.8v3.8M199.3 92.1v1.9"/>
<path d="M199.3 97.8v3.8M201.2 97.8v3.8M205 97.8v3.8M206.9 92.1v1.9M206.9 97.8v3.8M208.8 97.8v3.8M224 92.1v1.9M224 97.8v1.9M237.3 84.5h1.9M243 84.5h1.9M248.7 86.4v2.2M248.7 89.8v2.3"/>
<path d="M248.7 94v1.9M261 97.3h1.9v.9h-1.9zM261.9 86.4v1.9M261.9 89v3.1M261.9 94v1.9M261.9 99.7v1.9M262.9 97.8h2.8M279 97.8h2.9l.9 .9 1-.9M279 99.7h4.8l.9-1 1 1M290.4 86h2.8M11.5 118.6h1.9M21 114.8h1.8"/>
<path d="M21 116.7h1.8M21 118.6h1.8M28.5 114.8h1.9M28.5 101.2v2.3M28.5 105.3v2M36.1 101.2v2.3M36.1 105.3v2M47.5 107.3v1.8M49.4 105.3h1.9M51.3 118.6h1.9M55.1 105.3h1.9M57 118.6h1.9"/>
<path d="M62.7 101.6v1.9M64.6 107.3v1.8M70.3 109.1h3.8M70.3 111h3.8M70.3 116.7h3.8M70.3 118.6h3.8M70.3 105.3h3.8M106.3 109.1h3.8M106.3 111h3.8M106.3 112.9h3.8M106.3 114.8h3.8M106.3 116.7h3.8"/>
<path d="M106.3 118.6h3.8M106.3 105.3h3.8M106.3 107.3h3.8M125.3 114.8v1.9M129.1 114.8v1.9M132.9 114.8v1.9M136.7 114.8v1.9M140.5 114.8v1.9M161.4 103.1v2.2M161.4 107.3v1.8M178.5 109.1h3.7M178.5 111h3.7"/>
<path d="M178.5 112.9h3.7M178.5 114.8h3.7M178.5 116.7h3.7M178.5 118.6h3.7M214.5 109.1h3.8M214.5 111h3.8M214.5 112.9h3.8M214.5 114.8h3.8M214.5 116.7h3.8M214.5 118.6h3.8M224 103.5v1.8M261.9 105.3v2"/>
<path d="M261.9 111v1.9M261.9 114.8v2.3M261.9 118.3v2.2M279 101.6h7.6M3.9 123.8h2.8M21 120.5h1.8M21 122.4h1.8M28.5 122.4h1.9M36.1 122.4h1.9M43.7 120.5h1.9M43.7 135.7v1.9M45.6 128.1h2.3"/>
<path d="M45.6 135.7h2.3M49 128.1h2.3M49 135.7h2.3M49.4 120.5h1.9M55.1 130v1.1M55.1 132.7v1.1M70.3 120.5h3.8M70.3 128.1h3.8M70.3 135.7h3.8M106.3 122.4h3.8M106.3 124.3h3.8M106.3 126.2h3.8"/>
<path d="M106.3 128.1h3.8M106.3 130h3.8M106.3 133.8h3.8M106.3 135.7h3.8M106.3 137.6h3.8M106.3 139.5h3.8M125.3 120.5v1.9M129.1 120.5v1.9M132.9 120.5v1.9M136.7 120.5v1.9M140.5 120.5v1.9M150 133.8v1.9"/>
<path d="M151.9 120.5h2.3M151.9 131.9h2.3M155.3 120.5h2.3M155.3 131.9h2.3M159.5 124.3v1.2M159.5 127v1.1M163.3 122.4v1.9M163.3 128.1v1.9M178.5 120.5h3.7M178.5 122.4h3.7M178.5 124.3h3.7M178.5 126.2h3.7"/>
<path d="M178.5 128.1h3.7M178.5 130h3.7M178.5 131.9h3.7M178.5 133.8h3.7M178.5 135.7h3.7M178.5 139.5v1.9M214.5 120.5h3.8M214.5 122.4h3.8M214.5 124.3h3.8M214.5 130h3.8M214.5 131.9h3.8M214.5 133.8h3.8"/>
<path d="M214.5 135.7h3.8M222.1 137.6v1.9M229.7 135.7v2.3M229.7 139.1v2.3M244.9 130h1.9M250.5 130h2M254.4 131.9v2.3M254.4 135.3v2.3M254.4 139.5v1.9M261.9 122.4v1.9M261.9 130v1.9M261.9 132.7v3"/>
<path d="M261.9 137.6v1.9M290.4 123.8h2.8M55.1 141.4v2.3M55.1 144.8v4.2M64.6 147.1v1.9M70.3 141.4h3.8M70.3 145.2h3.8M70.3 147.1h3.8M106.3 141.4h3.8M106.3 145.2h3.8M106.3 147.1h3.8M106.3 143.3h3.8"/>
<path d="M125.3 147.1v1.9M125.3 152.8v1.9M129.1 147.1v1.9M129.1 152.8v1.9M132.9 147.1v1.9M132.9 152.8v1.9M136.7 147.1v1.9M136.7 152.8v1.9M140.5 147.1v1.9M140.5 152.8v1.9M143.7 156.2h.1M143.7 156.1h.3"/>
<path d="M143.7 156.1h.5M143.7 157.1h.1M143.8 156h.5M143.8 157.1h.2M143.8 155.9h.4M143.8 157h.4M143.8 155.8h.3M143.8 156.9h.6M143.9 155.7h.1M143.9 156.8h.4M143.9 155.6l.4 .4-.7 .3zM143.9 156.7h.4"/>
<path d="M144 156.6h.2M144 156.5h.1M144 156.5l.4 .4-.7 .2zM144.7 155.3l-1.1 1M144.8 156.1l-1.1 1M146.2 143.3v1.9M146.2 149v1.9M146.2 152.8v1.9M146.2 156.6v1.9M170.9 143.3v1.9M170.9 149v1.9M170.9 154.7v1.9"/>
<path d="M178.5 145.2v1.9M178.5 154.7v1.9M186 147.1v3.8M187.9 147.1v3.8M189.8 147.1v3.8M191.7 147.1v3.8M191.7 154.7v1.9M193.6 147.1v3.8M195.5 147.1v3.8M203.1 147.1v3.8M205 147.1v3.8M205 154.7v1.9"/>
<path d="M206.9 147.1v3.8M208.8 147.1v3.8M222.1 143.3v1.9M222.1 154.7v1.9M229.7 154.7v1.9M246.8 158.5v1.9M261 140.9h1.9v1h-1.9zM261.9 143.3v1.9M261.9 158.5v1.9M262.9 141.4h2.8M263.8 156.6h1.9M267.2 155.6h.9v1.9h-.9z"/>
<path d="M267.6 152.8v2.8M269.5 156.6h1.9M3.9 161.5h2.8M132.9 164.2v1.9M146.2 164.2v1.9M246.8 164.2v1.9M246.8 168v2.2M246.8 171.4v2.3M246.8 175.6v1.9M261.9 164.2v1.9M261.9 168v2.2M261.9 171.4v2.3"/>
<path d="M261.9 175.6v1.9M275.2 162.3v1.9M290.4 161.5h2.8M42.2 199.3v2.8M77.6 199.3v2.8M113.1 199.3v2.8M148.6 199.3v2.8M184 199.3v2.8M219.5 199.3v2.8M255 199.3v2.8M259.6 195.5h30.8M259.6 184.1v15.2"/>
<path d="M259.6 191.7h30.8M259.6 187.9h30.8M282.8 195.5v3.8M290.4 184.1h-71.2v15.2"/>
</g>
<g fill="#800000" stroke="#800000" stroke-width=".16">
<path d="M120 31.2h3v.3h-3z"/>
<path d="M120 30.4h3v.4h-3z"/>
<path d="M112.2 28.9h.7v.1h-.7z"/>
<path d="M112.5 28.6h.1v.7h-.1z"/>
<path d="M112.2 53.5h.7v.1h-.7z"/>
<path d="M112.5 53.2h.1v.7h-.1z"/>
<path d="M120 55.3h3v.3h-3z"/>
<path d="M120 54.5h3v.4h-3z"/>
<path d="M154.9 119h.4v3h-.4z"/>
<path d="M154.2 119h.3v3h-.3z"/>
<path d="M154.9 130.4h.4v3h-.4z"/>
<path d="M154.2 130.4h.3v3h-.3z"/>
<path d="M228.2 138h3v.4h-3z"/>
<path d="M228.2 138.7h3v.4h-3z"/>
<path d="M245.2 171h3.1v.4h-3.1z"/>
<path d="M245.2 170.2h3.1v.4h-3.1z"/>
<path d="M260.4 117.9h3.1v.4h-3.1z"/>
<path d="M260.4 117.1h3.1v.4h-3.1z"/>
<path d="M260.4 171h3.1v.4h-3.1z"/>
<path d="M260.4 170.2h3.1v.4h-3.1z"/>
<path d="M106.7 40.1h3.1v.3h-3.1z"/>
<path d="M106.7 39.3h3.1v.4h-3.1z"/>
<path d="M127.6 31.2h3v.3h-3z"/>
<path d="M127.6 30.4h3v.4h-3z"/>
<path d="M135.2 31.2h3v.3h-3z"/>
<path d="M135.2 30.4h3v.4h-3z"/>
<path d="M142.8 31.2h3v.3h-3z"/>
<path d="M142.8 30.4h3v.4h-3z"/>
<path d="M127.6 55.3h3v.3h-3z"/>
<path d="M127.6 54.5h3v.4h-3z"/>
<path d="M286 97.7h1.2v3.9h-1.2z"/>
<path d="M53.6 144.4h3v.4h-3z"/>
<path d="M53.6 143.7h3v.4h-3z"/>
<path d="M48.7 126.6h.3v3h-.3z"/>
<path d="M47.9 126.6h.4v3h-.4z"/>
<path d="M48.7 134.2h.3v3h-.3z"/>
<path d="M47.9 134.2h.4v3h-.4z"/>
<path d="M76.3 38.2h3.1v.4h-3.1z"/>
<path d="M76.3 37.4h3.1v.4h-3.1z"/>
<path d="M30.6 34.6h.7h-.7z"/>
<path d="M30.9 34.3h.1v.6h-.1z"/>
<path d="M242.2 30.4h.4v1.9h-.4z"/>
<path d="M241.4 30.4h.4v1.9h-.4z"/>
<path d="M242.2 34.2h.4v1.9h-.4z"/>
<path d="M241.4 34.2h.4v1.9h-.4z"/>
<path d="M228.9 38h.4v1.9h-.4z"/>
<path d="M228.2 38h.3v1.9h-.3z"/>
<path d="M228.9 41.8h.4v1.9h-.4z"/>
<path d="M228.2 41.8h.3v1.9h-.3z"/>
<path d="M240.3 55.1h.4v1.9h-.4z"/>
<path d="M239.5 55.1h.4v1.9h-.4z"/>
<path d="M236.5 57h.4v1.9h-.4z"/>
<path d="M235.8 57h.3v1.9h-.3z"/>
<path d="M27 100.8h3.1v.4h-3.1z"/>
<path d="M27 100h3.1v.4h-3.1z"/>
<path d="M34.6 100.8h3.1v.4h-3.1z"/>
<path d="M34.6 100h3.1v.4h-3.1z"/>
<path d="M159.9 102.7h3v.4h-3z"/>
<path d="M159.9 101.9h3v.4h-3z"/>
<path d="M261 97.3h1.9v.9h-1.9z"/>
<path d="M261 140.9h1.9v1h-1.9z"/>
<path d="M267.2 155.6h.9v1.9h-.9z"/>
<path d="M260.2 87.7h.7v.1h-.7z"/>
<path d="M260.5 87.4h.1v.7h-.1z"/>
<path d="M260.2 131.3h.7v.1h-.7z"/>
<path d="M260.5 131h.1v.7h-.1z"/>
<path d="M247.1 89.4h3.1v.4h-3.1z"/>
<path d="M247.1 88.6h3.1v.4h-3.1z"/>
<path d="M252.8 135h3.1v.3h-3.1z"/>
<path d="M252.8 134.2h3.1v.4h-3.1z"/>
</g>
<g fill="none" stroke="#800000" stroke-width=".19">
<path d="M30.4 35.1h3.8M38 29.4h11.4v7.6h-11.4zM56.3 35.1h1.4v3.8h-1.4zM65.6 30.4l1.8 .9-1.8 1zM65.6 24.7l1.8 1-1.8 .9zM66.5 35.1h5.7v5.7h-5.7v-.7h1.9v-4.2h-1.9zM67.9 30.6v-.2h-.5v1.9h-.4v-.2M67.9 24.9v-.2h-.5v1.9h-.4v-.2M68.8 37h.7M68.8 38.9h.7M69.2 36.7v.7M69.7 35.1v.6h1.2v-.6"/>
<path d="M89.7 37h2.9M112 29.4h3.8M112.5 37h2.9M120.1 37h2.8M127.7 37h2.8M135.3 37h2.8M142.9 37h2.8M143.7 22.8l.6-.9 .6 .9M189.3 30.4l.5-1 .6 1M195.5 31.3h9.5v26.6h-9.5zM232.5 34.2l1-.9 .9 .9M248.7 29.4h11.4v30.4h-11.4z"/>
<path d="M30.9 44.6h2.9M49.9 44.6h2.8M55.6 44.6h2.8M61.3 44.6h2.8M69.7 40.8v-.5h1.2v.5M76.5 44.6h2.8M88.7 47.5l.6-1 .5 1M106.8 44.6h2.9M112 54.1h3.8M128.5 47.5l.6-1 .6 1M188.4 59.8h2.9M195.9 52.2h.9v3.8h-.9"/>
<path d="M229.7 53.2h3.8v1.9h-3.8zM89.7 63.6h2.9M112.5 61.7h2.9M120.1 61.7h2.8M127.7 61.7h2.8M224.9 61.7h1.9M35.6 93l.5-.9 .6 .9M62 97.8h1.4v3.8h-1.4zM62.1 93l.6-.9 .6 .9M168.4 93l.6-.9 .5 .9M189.3 93l.5-.9 .6 .9M198.8 93l.5-.9 .6 .9"/>
<path d="M206.4 93l.5-.9 .6 .9M223.3 99.7h1.4v3.8h-1.4zM223.4 93l.6-.9 .6 .9M239.2 83.8h3.8v1.3h-3.8zM247.2 95.9h2.9M260.1 88.3h3.7M261.9 95.9v1.9M27.1 107.3h2.9M30.4 113.4v2.9M34.7 107.3h2.8M45.6 119.9h3.8v1.3h-3.8zM46.1 109.1h2.8"/>
<path d="M53.2 118h3.8v1.3h-3.8zM54.6 105.3h.5M54.6 104.4l-3.3 .9M64 108.2l.6-.9 .6 .9M74.1 103.5h32.2v45.5h-32.2zM124.4 117.2l.9 3.3M125.3 116.7v.5M128.2 117.2l.9 3.3M129.1 116.7v.5M132 117.2l.9 3.3M132.3 100.6l.6-.9 .6 .9M132.9 116.7v.5"/>
<path d="M135.8 117.2l.9 3.3M136.7 116.7v.5M139.6 117.2l.9 3.3M140.5 116.7v.5M160 109.1h2.8M182.2 101.6h32.3v45.5h-32.3zM261.3 107.3h1.3v3.7h-1.3zM30.4 121.5h5.7v1.9h-5.7zM36.1 120.5h-.9l-4 3.8M42.3 137.6h2.8M53.8 131.1h2.6M53.8 132.7h2.6"/>
<path d="M54 131.6h2.2v.6h-2.2zM148.6 135.7h2.8M158.1 125.5h2.7M158.1 127h2.7M158.3 125.9h2.3v.6h-2.3zM162.6 124.3h1.3v3.8h-1.3zM221.4 139.5h1.4v3.8h-1.4zM246.8 129.3h3.7v1.4h-3.7zM260.1 131.9h3.7M260.5 124.3h2.9M261.9 139.5v1.9M53.7 149h2.8"/>
<path d="M63.2 149h2.8M124.7 149h1.3v3.8h-1.3zM128.4 149h1.4v3.8h-1.4zM132.2 149h1.4v3.8h-1.4zM136 149h1.4v3.8h-1.4zM139.8 149h1.4v3.8h-1.4zM145.2 156.6h2M145.2 154.7h2l-1 1.9zM145.5 145.2h1.4v3.8h-1.4zM169.4 156.6h2.9M170.2 145.2h1.3v3.8h-1.3zM177 156.6h2.9"/>
<path d="M177.8 141.4h1.3v3.8h-1.3zM190.3 156.6h2.8M203.6 156.6h2.8M220.7 156.6h2.8M228.3 156.6h2.8M252.9 141.4h2.9M267.6 156.6h1.9M131.5 166.1h2.8M144.8 166.1h2.8M245.3 177.5h2.9M246.1 160.4h1.3v3.8h-1.3zM260.5 177.5h2.9"/>
<path d="M261.3 160.4h1.3v3.8h-1.3zM273.8 164.2h2.8"/>
</g>
<g fill="#800000" stroke="#800000" stroke-width=".16">
<path d="M113.9 30.1l1.4 .3 .5 .4-.1 .1a3.1 3.1 0 0 0-1.8-.6z" fill-rule="evenodd"/>
<path d="M112 30.8l1.3-.6 .6-.1v.2a2.93 2.93 0 0 0-1.8 .6z" fill-rule="evenodd"/>
<path d="M113.9 54.8h.2a2.74 2.74 0 0 1 1.7 .6l-.1 .2a2.78 2.78 0 0 0-1.8-.6z" fill-rule="evenodd"/>
<path d="M112 55.4l.5-.3 .8-.3h.6v.2a2.78 2.78 0 0 0-1.8 .6z" fill-rule="evenodd"/>
<path d="M32.3 35.8l1.4 .3 .5 .3-.1 .2a3.1 3.1 0 0 0-1.8-.6z" fill-rule="evenodd"/>
<path d="M30.4 36.4l1.3-.5 .6-.1v.2a2.93 2.93 0 0 0-1.8 .6z" fill-rule="evenodd"/>
<path d="M51.1 105.2h.4l.1 .1-.1 .2-.2 .1-.2-.1z" fill-rule="evenodd"/>
<path d="M54.9 105.2h.4v.3l-.2 .1-.2-.1z" fill-rule="evenodd"/>
<path d="M125.1 120.4h.4v.3h-.4z" fill-rule="evenodd"/>
<path d="M125.1 116.6l.2-.1 .2 .1v.3l-.2 .1-.2-.1z" fill-rule="evenodd"/>
<path d="M128.9 120.4h.4v.3h-.4v-.2z" fill-rule="evenodd"/>
<path d="M132.7 120.4h.4l.1 .1-.1 .2h-.4v-.2z" fill-rule="evenodd"/>
<path d="M136.5 120.4h.4v.3h-.4z" fill-rule="evenodd"/>
<path d="M136.5 116.6l.2-.1 .2 .1v.3l-.2 .1-.2-.1z" fill-rule="evenodd"/>
<path d="M261.2 96.1a.95 .95 0 0 1 1.1-.3 .95 .95 0 0 1 .6 .9h-1.9z" fill-rule="evenodd"/>
<path d="M261 98.8h1.9a.95 .95 0 0 1-1 1 .95 .95 0 0 1-.9-1z" fill-rule="evenodd"/>
<path d="M261.2 139.7a.96 .96 0 0 1 1.1-.2 .96 .96 0 0 1 .6 .9h-1.9z" fill-rule="evenodd"/>
<path d="M261 142.5h1.9a.95 .95 0 0 1-1 .9 .95 .95 0 0 1-.9-.9z" fill-rule="evenodd"/>
<path d="M268.7 155.6a.94 .94 0 0 1 .9 1 .94 .94 0 0 1-.9 .9z" fill-rule="evenodd"/>
<path d="M266 155.9l.6-.3v1.9a.95 .95 0 0 1-.9-.6 .95 .95 0 0 1 .3-1z" fill-rule="evenodd"/>
<path d="M261.9 88.9l1.4 .3 .6 .4-.2 .1a3.1 3.1 0 0 0-1.8-.6z" fill-rule="evenodd"/>
<path d="M260 89.6l1.3-.6 .6-.1v.2a2.93 2.93 0 0 0-1.7 .6z" fill-rule="evenodd"/>
<path d="M261.9 132.6l1.4 .3 .6 .3-.2 .2a2.78 2.78 0 0 0-1.8-.6z" fill-rule="evenodd"/>
<path d="M260 133.2l.6-.3 .7-.3h.6v.2a2.93 2.93 0 0 0-1.7 .6z" fill-rule="evenodd"/>
<path d="M140.3 120.4h.4v.3h-.4z" fill-rule="evenodd"/>
<path d="M140.3 116.6l.2-.1 .2 .1v.3l-.2 .1-.2-.1z" fill-rule="evenodd"/>
<circle cx="129.1" cy="116.7" r=".25"/>
<circle cx="132.9" cy="116.7" r=".25"/>
</g>
<path d="M3.9 7.6h289.3v194.5h-289.3z" fill="none" stroke="#800000" stroke-width=".23"/>
<path d="M13.4 112.9h7.6v11.4h-7.6z" fill="none" stroke="#800000" stroke-width=".38"/>
<g fill="none" stroke="#008000" stroke-width=".16">
<path d="M26.6 25.7h38M32.3 25.7v7.6M32.3 38.9v3.8M32.3 31.3h3.8M51.3 33.3h5.7M51.3 35.1v7.6M51.3 31.3h13.3M62.7 31.3v5.7h1.9M64.6 38.9h-1.9v3.8M68.4 25.7h24.7M68.4 31.3h9.5M77.9 25.7v9.4"/>
<path d="M89.3 25.7v3.7h3.8M93.1 33.3h-1.9v1.8M106.3 33.3h1.9v3.7M106.3 25.7h38M113.9 25.7v1.9M113.9 33.3v1.8M121.5 25.7v2.4M121.5 33.8v1.3M129.1 25.7v2.4M129.1 33.8v1.3M136.7 25.7v2.4M136.7 33.8v1.3"/>
<path d="M144.3 23.7v4.4M144.3 33.8v1.3M186 37h5.7M186 35.1h5.7M189.8 31.3v7.6h1.9M225.9 38.9v20.9M231.6 38.9h15.2M233.5 35.1v7.6M239.2 31.3h-1.9v2h9.5M239.2 35.1h-1.9v1.9h9.5M244.9 31.3h1.9M244.9 35.1h1.9"/>
<path d="M57 40.8v1.9M77.9 40.8v1.9M89.3 48.4v5.7h3.8M89.3 50.3h3.8M93.1 57.9h-1.9v3.8M106.3 50.3h22.8M113.9 50.3v1.9M113.9 57.9v1.9M121.5 50.3v1.9M121.5 57.9v1.9M129.1 48.4v3.8M129.1 57.9v1.9"/>
<path d="M186 40.8h5.7M186 44.6h5.7M189.8 56h1.9M189.8 54.1h1.9M189.8 52.2h1.9M189.8 50.3h1.9M191.7 42.7h-1.9v15.2M225.9 57.9h7.6M225.9 56h11.4M225.9 54.1h1.9M225.9 40.8h20.9M231.6 42.7h15.2"/>
<path d="M235.4 54.1h11.4M239.2 57.9h7.6M243 56h3.8M244.9 52.2h1.9M244.9 50.3h1.9M244.9 44.6h1.9M244.9 46.5h1.9M244.9 48.4h1.9M36.1 95.9h-7.6v1.9M36.1 94v3.8M62.7 94v1.9M169 97.8h-7.6v1.9"/>
<path d="M169 94v28.4h9.5M187.9 97.8v-1.9h3.8v1.9M189.8 94v3.8M195.5 97.8v-1.9h5.7v1.9M197.4 95.9v1.9M199.3 94v3.8M205 97.8v-1.9h3.8v1.9M206.9 94v3.8M224 94v3.8M235.4 84.5h1.9M244.9 84.5h17v1.9M248.7 84.5v1.9"/>
<path d="M248.7 92.1v1.9M261.9 92.1v1.9M265.7 97.8h13.3M279 99.7h-13.3v41.7M22.8 114.8h5.7M22.8 118.6h28.5M28.5 103.5v1.8M36.1 103.5v1.8M49.4 105.3h-1.9v2M57 105.3h13.3M58.9 118.6h11.4M62.7 103.5v1.8"/>
<path d="M64.6 111h5.7M70.3 109.1h-5.7v7.6h5.7M110.1 105.3h3.8M110.1 114.8h3.8M110.1 109.1h3.8M110.1 112.9h3.8M110.1 116.7h3.8M110.1 111h3.8M110.1 107.3h3.8M110.1 118.6h3.8M125.3 114.8v-9.5h15.2v9.5M129.1 105.3v9.5"/>
<path d="M132.9 101.6v13.2M136.7 105.3v9.5M161.4 105.3v2M218.3 114.8h3.8M218.3 112.9h3.8M218.3 116.7h3.8M224 105.3v3.8h-5.7M233.5 103.5h28.4M261.9 101.6v3.7M261.9 112.9v1.9M279 101.6h-11.4v51.2M22.8 120.5h20.9"/>
<path d="M22.8 122.4h5.7M38 122.4h17.1M45.6 128.1h-1.9v7.6h1.9M51.3 120.5h19M51.3 135.7h19M51.3 128.1h19M55.1 128.1v1.9M55.1 133.8v1.9M110.1 135.7h3.8M110.1 128.1h3.8M110.1 133.8h36.1v9.5M110.1 126.2h3.8"/>
<path d="M110.1 139.5h19M110.1 137.6h15.2M125.3 122.4v24.7M129.1 122.4v24.7M132.9 122.4v24.7M140.5 122.4v24.7M150 131.9h1.9M151.9 120.5h-1.9v13.3M157.6 120.5h9.5v3.8h11.4M159.5 120.5v3.8M159.5 128.1v3.8M163.3 120.5v1.9"/>
<path d="M163.3 130v1.9M167.1 139.5h3.8v3.8M178.5 126.2h-11.4v5.7h-9.5M178.5 130v9.5M218.3 131.9h3.8M218.3 124.3h11.4v11.4M218.3 130h3.8v7.6M218.3 135.7h3.8M218.3 133.8h3.8M241.1 130h3.8M252.5 130h9.4M254.4 130v1.9"/>
<path d="M254.4 137.6v1.9M261.9 120.5v1.9M261.9 135.7v1.9M55.1 141.4h15.2M64.6 147.1h5.7M70.3 145.2h-3.8v1.9M110.1 143.3h26.6v3.8M110.1 145.2h30.4M110.1 147.1h3.8M110.1 141.4h22.8M125.3 154.7v5.7h15.2v-5.7M129.1 154.7v5.7"/>
<path d="M132.9 154.7v9.5M136.7 154.7v5.7M146.2 150.9v1.9M146.2 158.5v5.7M170.9 150.9v3.8M178.5 147.1v7.6M186 150.9v1.9h9.5v-1.9M187.9 150.9v1.9M189.8 150.9v1.9M191.7 150.9v3.8M193.6 150.9v1.9M203.1 150.9v1.9h5.7v-1.9"/>
<path d="M205 150.9v3.8M206.9 150.9v1.9M222.1 145.2v9.5M229.7 141.4v13.3M246.8 152.8v5.7M260.1 156.6h3.7M261.9 145.2v7.6h-20.8M261.9 156.6v1.9M271.4 156.6h3.8v5.7M246.8 166.1v1.9M246.8 173.7v1.9M261.9 166.1v1.9"/>
<path d="M261.9 173.7v1.9"/>
</g>
<g fill="#008000" stroke="#008000" stroke-width=".16">
<circle cx="193.6" cy="152.8" r=".38"/>
<circle cx="191.7" cy="152.8" r=".38"/>
<circle cx="189.8" cy="152.8" r=".38"/>
<circle cx="187.9" cy="152.8" r=".38"/>
<circle cx="205" cy="152.8" r=".38"/>
<circle cx="206.9" cy="152.8" r=".38"/>
<circle cx="150" cy="131.9" r=".38"/>
<circle cx="189.8" cy="56" r=".38"/>
<circle cx="189.8" cy="54.1" r=".38"/>
<circle cx="189.8" cy="52.2" r=".38"/>
<circle cx="189.8" cy="50.3" r=".38"/>
<circle cx="43.7" cy="135.7" r=".38"/>
<circle cx="66.5" cy="147.1" r=".38"/>
<circle cx="225.9" cy="54.1" r=".38"/>
<circle cx="225.9" cy="57.9" r=".38"/>
<circle cx="225.9" cy="56" r=".38"/>
<circle cx="225.9" cy="42.7" r=".38"/>
<circle cx="225.9" cy="40.8" r=".38"/>
<circle cx="132.9" cy="160.4" r=".38"/>
<circle cx="129.1" cy="160.4" r=".38"/>
<circle cx="136.7" cy="160.4" r=".38"/>
<circle cx="163.3" cy="120.5" r=".38"/>
<circle cx="159.5" cy="120.5" r=".38"/>
<circle cx="163.3" cy="131.9" r=".38"/>
<circle cx="159.5" cy="131.9" r=".38"/>
<circle cx="261.9" cy="103.5" r=".38"/>
<circle cx="246.8" cy="152.8" r=".38"/>
<circle cx="261.9" cy="156.6" r=".38"/>
<circle cx="113.9" cy="25.7" r=".38"/>
<circle cx="121.5" cy="25.7" r=".38"/>
<circle cx="136.7" cy="25.7" r=".38"/>
<circle cx="129.1" cy="25.7" r=".38"/>
<circle cx="144.3" cy="25.7" r=".38"/>
<circle cx="206.9" cy="95.9" r=".38"/>
<circle cx="189.8" cy="95.9" r=".38"/>
<circle cx="169" cy="97.8" r=".38"/>
<circle cx="89.3" cy="50.3" r=".38"/>
<circle cx="64.6" cy="111" r=".38"/>
<circle cx="64.6" cy="109.1" r=".38"/>
<circle cx="233.5" cy="38.9" r=".38"/>
<circle cx="233.5" cy="42.7" r=".38"/>
<circle cx="36.1" cy="95.9" r=".38"/>
<circle cx="129.1" cy="105.3" r=".38"/>
<circle cx="132.9" cy="105.3" r=".38"/>
<circle cx="136.7" cy="105.3" r=".38"/>
<circle cx="113.9" cy="50.3" r=".38"/>
<circle cx="121.5" cy="50.3" r=".38"/>
<circle cx="129.1" cy="50.3" r=".38"/>
<circle cx="199.3" cy="95.9" r=".38"/>
<circle cx="197.4" cy="95.9" r=".38"/>
<circle cx="178.5" cy="131.9" r=".38"/>
<circle cx="178.5" cy="133.8" r=".38"/>
<circle cx="178.5" cy="135.7" r=".38"/>
<circle cx="222.1" cy="135.7" r=".38"/>
<circle cx="222.1" cy="131.9" r=".38"/>
<circle cx="222.1" cy="133.8" r=".38"/>
<circle cx="178.5" cy="111" r=".38"/>
<circle cx="178.5" cy="112.9" r=".38"/>
<circle cx="178.5" cy="109.1" r=".38"/>
<circle cx="178.5" cy="114.8" r=".38"/>
<circle cx="178.5" cy="116.7" r=".38"/>
<circle cx="178.5" cy="120.5" r=".38"/>
<circle cx="178.5" cy="118.6" r=".38"/>
<circle cx="62.7" cy="105.3" r=".38"/>
<circle cx="55.1" cy="128.1" r=".38"/>
<circle cx="55.1" cy="135.7" r=".38"/>
<circle cx="62.7" cy="31.3" r=".38"/>
<circle cx="77.9" cy="25.7" r=".38"/>
<circle cx="89.3" cy="25.7" r=".38"/>
<circle cx="77.9" cy="31.3" r=".38"/>
<circle cx="125.3" cy="137.6" r=".38"/>
<circle cx="129.1" cy="139.5" r=".38"/>
<circle cx="132.9" cy="141.4" r=".38"/>
<circle cx="32.3" cy="31.3" r=".38"/>
<circle cx="32.3" cy="25.7" r=".38"/>
<circle cx="140.5" cy="145.2" r=".38"/>
<circle cx="254.4" cy="130" r=".38"/>
<circle cx="248.7" cy="84.5" r=".38"/>
</g>
<use href="#words"/>
</svg>
